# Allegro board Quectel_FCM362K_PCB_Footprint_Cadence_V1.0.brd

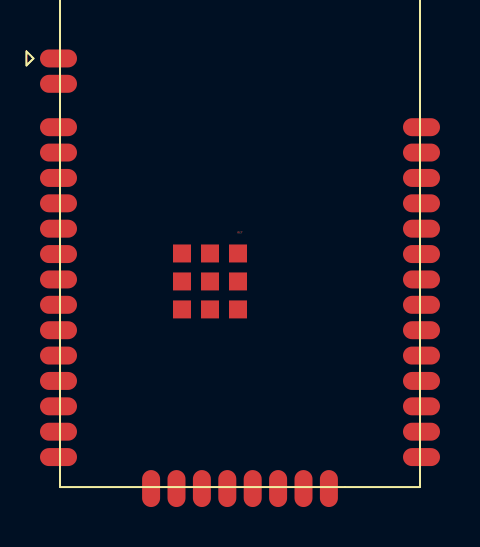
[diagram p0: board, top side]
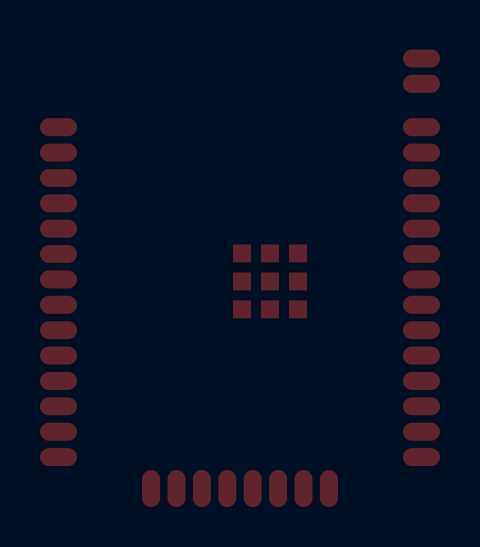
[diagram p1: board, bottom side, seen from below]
No outline. copper layers: TOP, BOTTOM. Coordinates in mm from the lowest, leftmost part position.

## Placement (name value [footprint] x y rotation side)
REF  -  [unnamed]  0 0 0 top

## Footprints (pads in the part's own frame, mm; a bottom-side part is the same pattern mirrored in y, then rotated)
unnamed
  oval 1.85x0.9 smd: 1(-9.075,8.7) 2(-9.075,7.43) 3(-9.075,5.26) 4(-9.075,3.99) 5(-9.075,2.72) 6(-9.075,1.45) 7(-9.075,0.18) 8(-9.075,-1.09) 9(-9.075,-2.36) 10(-9.075,-3.63) 11(-9.075,-4.9) 12(-9.075,-6.17) 13(-9.075,-7.44) 14(-9.075,-8.71) 15(-9.075,-9.98) 16(-9.075,-11.25) 25(9.075,-11.25) 26(9.075,-9.98) 27(9.075,-8.71) 28(9.075,-7.44) 29(9.075,-6.17) 30(9.075,-4.9) 31(9.075,-3.63) 32(9.075,-2.36) 33(9.075,-1.09) 34(9.075,0.18) 35(9.075,1.45) 36(9.075,2.72) 37(9.075,3.99) 38(9.075,5.26)
  oval 0.9x1.85 smd: 17(-4.445,-12.825) 18(-3.175,-12.825) 19(-1.905,-12.825) 20(-0.635,-12.825) 21(0.635,-12.825) 22(1.905,-12.825) 23(3.175,-12.825) 24(4.445,-12.825)
  rect 0.9x0.9 smd: 39(-2.9,-1.06) 40(-2.9,-2.46) 41(-2.9,-3.86) 42(-1.5,-1.06) 43(-1.5,-2.46) 44(-1.5,-3.86) 45(-0.1,-1.06) 46(-0.1,-2.46) 47(-0.1,-3.86)

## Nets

Pads without a net: REF 1 2 3 4 5 6 7 8 9 10 11 12 13 14 15 16 17 18 19 20 21 22 23 24 25 26 27 28 29 30 31 32 33 34 35 36 37 38 39 40 41 42 43 44 45 46 47
